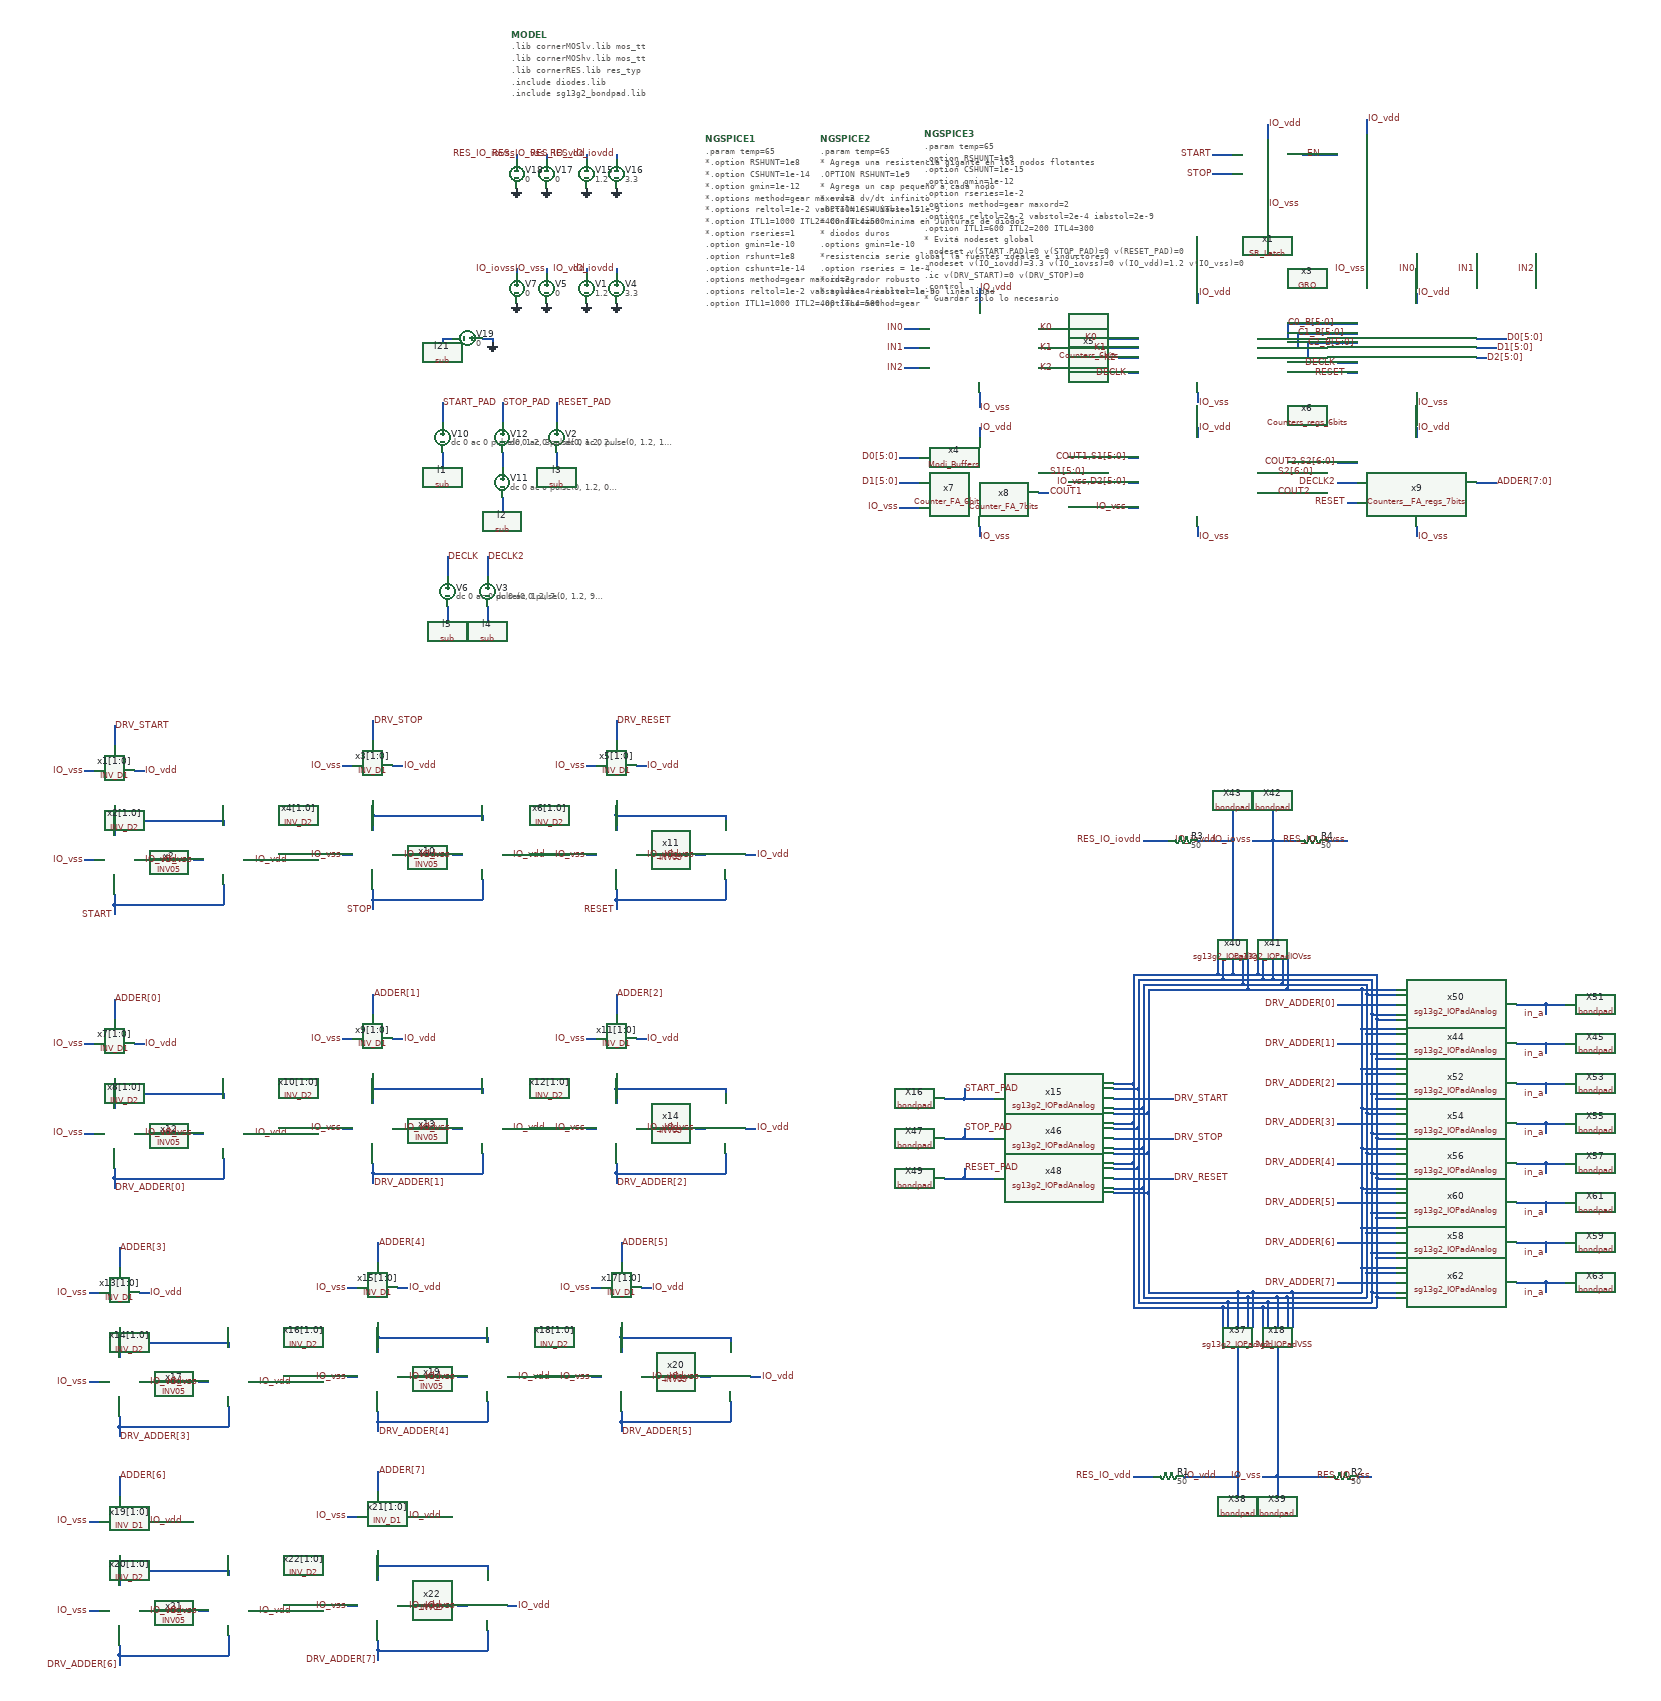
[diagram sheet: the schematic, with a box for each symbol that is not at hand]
v {xschem version=3.4.8RC file_version=1.3}
G {}
K {}
V {}
S {}
F {}
E {}
B 2 30 -920 830 -520 {flags=graph
y2=1.5
ypos1=0
ypos2=2
divy=5
subdivy=1
unity=1
x1=0
divx=5
subdivx=1


dataset=-1
unitx=1
logx=0
logy=0
hilight_wave=0


y1=-0.2
color="17 8 10"
node="IN0
IN1
IN2"
x2=1.1e-07}
B 2 30 -470 830 -70 {flags=graph
y2=1.5
ypos1=0
ypos2=2
divy=5
subdivy=1
unity=1
x1=0
x2=1.1e-07
divx=5
subdivx=1


dataset=-1
unitx=1
logx=0
logy=0
hilight_wave=0


y1=-0.2
color="17 8 10"
node="K0
K1
K2"}
B 2 30 -1360 830 -960 {flags=graph
y2=1.5
ypos1=0
ypos2=2
divy=5
subdivy=1
unity=1
x1=0
x2=1.1e-07
divx=5
subdivx=1


dataset=-1
unitx=1
logx=0
logy=0
hilight_wave=0


y1=-0.2
color="17 8 10 11 15"
node="START
STOP
DECLK
EN
RESET"}
B 2 20 -3140 820 -2740 {flags=graph
y1=-0.024
y2=1.3
ypos1=0
ypos2=2
divy=5
subdivy=1
unity=1
x1=0
x2=1.1e-07
divx=5
subdivx=1


dataset=-1
unitx=1
logx=0
logy=0
hilight_wave=0
color="10 11 11"
node="C0_B[1]
C1_B[1]
C2_B[1]"}
B 2 20 -1810 820 -1410 {flags=graph
y1=-0.4
y2=1.5
ypos1=0
ypos2=2
divy=5
subdivy=1
unity=1
x1=0
x2=1.1e-07
divx=5
subdivx=1


dataset=-1
unitx=1
logx=0
logy=0
hilight_wave=0
color="8 7 11"
node="C0_B[4]
C1_B[4]
C2_B[4]"
rainbow=1}
B 2 20 -2720 820 -2320 {flags=graph
y1=-0.4
y2=1.5
ypos1=0
ypos2=2
divy=5
subdivy=1
unity=1
x1=0
x2=1.1e-07
divx=5
subdivx=1


dataset=-1
unitx=1
logx=0
logy=0
hilight_wave=0
color="7 11 10"
node="C0_B[2]
C1_B[2]
C2_B[2]"}
B 2 20 -2260 820 -1860 {flags=graph
y1=-0.032
y2=1.3
ypos1=0
ypos2=2
divy=5
subdivy=1
unity=1
x1=0
x2=1.1e-07
divx=5
subdivx=1


dataset=-1
unitx=1
logx=0
logy=0
hilight_wave=0


color="11 10 7"
node="C0_B[3]
C1_B[3]
C2_B[3]"}
B 2 850 -3140 1650 -2740 {flags=graph
y1=-0.4
y2=1.5
ypos1=0
ypos2=2
divy=5
subdivy=1
unity=1
x1=0
x2=1.1e-07
divx=5
subdivx=1


dataset=-1
unitx=1
logx=0
logy=0
hilight_wave=0
color=10
node=D0[1]}
B 2 850 -3560 1650 -3160 {flags=graph
y1=-0.4
y2=1.5
ypos1=0
ypos2=2
divy=5
subdivy=1
unity=1
x1=0
x2=1.1e-07
divx=5
subdivx=1


dataset=-1
unitx=1
logx=0
logy=0
hilight_wave=0
color=8
node=D0[0]}
B 2 850 -1810 1650 -1410 {flags=graph
y1=-0.4
y2=1.5
ypos1=0
ypos2=2
divy=5
subdivy=1
unity=1
x1=0
x2=1.1e-07
divx=5
subdivx=1


dataset=-1
unitx=1
logx=0
logy=0
hilight_wave=0
color=8
node=D0[4]}
B 2 850 -2720 1650 -2320 {flags=graph
y1=-0.4
y2=1.5
ypos1=0
ypos2=2
divy=5
subdivy=1
unity=1
x1=0
x2=1.1e-07
divx=5
subdivx=1


dataset=-1
unitx=1
logx=0
logy=0
hilight_wave=0
color=7
node=D0[2]}
B 2 850 -2260 1650 -1860 {flags=graph
y1=-0.4
y2=1.5
ypos1=0
ypos2=2
divy=5
subdivy=1
unity=1
x1=0
x2=1.1e-07
divx=5
subdivx=1


dataset=-1
unitx=1
logx=0
logy=0
hilight_wave=0


color=11
node=D0[3]}
B 2 20 -3560 820 -3160 {flags=graph
y1=-0.4
y2=1.5
ypos1=0
ypos2=2
divy=5
subdivy=1
unity=1
x1=0
x2=1.1e-07
divx=5
subdivx=1


dataset=-1
unitx=1
logx=0
logy=0
hilight_wave=0
color="10 11 11"
node="C0_B[0]
C1_B[0]
C2_B[0]"}
B 2 1680 -3140 2480 -2740 {flags=graph
y1=-0.4
y2=1.5
ypos1=0
ypos2=2
divy=5
subdivy=1
unity=1
x1=0
x2=1.1e-07
divx=5
subdivx=1


dataset=-1
unitx=1
logx=0
logy=0
hilight_wave=0
color=10
node=D1[1]}
B 2 1680 -3560 2480 -3160 {flags=graph
y1=-0.4
y2=1.5
ypos1=0
ypos2=2
divy=5
subdivy=1
unity=1
x1=0
x2=1.1e-07
divx=5
subdivx=1


dataset=-1
unitx=1
logx=0
logy=0
hilight_wave=0
color=8
node=D1[0]}
B 2 1680 -1810 2480 -1410 {flags=graph
y1=-0.4
y2=1.5
ypos1=0
ypos2=2
divy=5
subdivy=1
unity=1
x1=0
x2=1.1e-07
divx=5
subdivx=1


dataset=-1
unitx=1
logx=0
logy=0
hilight_wave=0
color=8
node=D1[4]}
B 2 1680 -2720 2480 -2320 {flags=graph
y1=-0.4
y2=1.5
ypos1=0
ypos2=2
divy=5
subdivy=1
unity=1
x1=0
x2=1.1e-07
divx=5
subdivx=1


dataset=-1
unitx=1
logx=0
logy=0
hilight_wave=0
color=7
node=D1[2]}
B 2 1680 -2260 2480 -1860 {flags=graph
y1=-0.4
y2=1.5
ypos1=0
ypos2=2
divy=5
subdivy=1
unity=1
x1=0
x2=1.1e-07
divx=5
subdivx=1


dataset=-1
unitx=1
logx=0
logy=0
hilight_wave=0


color=11
node=D1[3]}
B 2 2520 -3140 3320 -2740 {flags=graph
y1=-0.4
y2=1.5
ypos1=0
ypos2=2
divy=5
subdivy=1
unity=1
x1=0
x2=1.1e-07
divx=5
subdivx=1


dataset=-1
unitx=1
logx=0
logy=0
hilight_wave=0
color=10
node=D2[1]}
B 2 2520 -3560 3320 -3160 {flags=graph
y1=-0.4
y2=1.5
ypos1=0
ypos2=2
divy=5
subdivy=1
unity=1
x1=0
x2=1.1e-07
divx=5
subdivx=1


dataset=-1
unitx=1
logx=0
logy=0
hilight_wave=0
color=8
node=D2[0]}
B 2 2520 -1810 3320 -1410 {flags=graph
y1=-0.4
y2=1.5
ypos1=0
ypos2=2
divy=5
subdivy=1
unity=1
x1=0
x2=1.1e-07
divx=5
subdivx=1


dataset=-1
unitx=1
logx=0
logy=0
hilight_wave=0
color=8
node=D2[4]}
B 2 2520 -2720 3320 -2320 {flags=graph
y1=-0.4
y2=1.5
ypos1=0
ypos2=2
divy=5
subdivy=1
unity=1
x1=0
x2=1.1e-07
divx=5
subdivx=1


dataset=-1
unitx=1
logx=0
logy=0
hilight_wave=0
color=7
node=D2[2]}
B 2 2520 -2260 3320 -1860 {flags=graph
y1=-0.4
y2=1.5
ypos1=0
ypos2=2
divy=5
subdivy=1
unity=1
x1=0
x2=1.1e-07
divx=5
subdivx=1


dataset=-1
unitx=1
logx=0
logy=0
hilight_wave=0


color=11
node=D2[3]}
B 2 3360 -3140 4160 -2740 {flags=graph
y1=-0.4
y2=1.5
ypos1=0
ypos2=2
divy=5
subdivy=1
unity=1
x1=0
x2=1.1e-07
divx=5
subdivx=1


dataset=-1
unitx=1
logx=0
logy=0
hilight_wave=0
color=10
node=S1[1]}
B 2 3360 -3560 4160 -3160 {flags=graph
y1=-0.4
y2=1.5
ypos1=0
ypos2=2
divy=5
subdivy=1
unity=1
x1=0
x2=1.1e-07
divx=5
subdivx=1


dataset=-1
unitx=1
logx=0
logy=0
hilight_wave=-1
color=8
node=S1[0]}
B 2 3360 -1810 4160 -1410 {flags=graph
y1=-0.4
y2=1.5
ypos1=0
ypos2=2
divy=5
subdivy=1
unity=1
x1=0
x2=1.1e-07
divx=5
subdivx=1


dataset=-1
unitx=1
logx=0
logy=0
hilight_wave=0
color=8
node=S1[4]}
B 2 3360 -1390 4160 -990 {flags=graph
y2=1.5
ypos1=0
ypos2=2
divy=5
subdivy=1
unity=1
x1=0
x2=1.1e-07
divx=5
subdivx=1


dataset=-1
unitx=1
logx=0
logy=0
hilight_wave=0
color=10
node=S1[5]
y1=-0.4}
B 2 3360 -2720 4160 -2320 {flags=graph
y1=-0.4
y2=1.5
ypos1=0
ypos2=2
divy=5
subdivy=1
unity=1
x1=0
x2=1.1e-07
divx=5
subdivx=1


dataset=-1
unitx=1
logx=0
logy=0
hilight_wave=0
color=7
node=S1[2]}
B 2 3360 -2260 4160 -1860 {flags=graph
y1=-0.4
y2=1.5
ypos1=0
ypos2=2
divy=5
subdivy=1
unity=1
x1=0
x2=1.1e-07
divx=5
subdivx=1


dataset=-1
unitx=1
logx=0
logy=0
hilight_wave=0


color=11
node=S1[3]}
B 2 4200 -3140 5000 -2740 {flags=graph
y1=-0.4
y2=1.5
ypos1=0
ypos2=2
divy=5
subdivy=1
unity=1
x1=0
x2=1.1e-07
divx=5
subdivx=1


dataset=-1
unitx=1
logx=0
logy=0
hilight_wave=0
color=10
node=S2[1]}
B 2 4200 -3560 5000 -3160 {flags=graph
y1=-0.4
y2=1.5
ypos1=0
ypos2=2
divy=5
subdivy=1
unity=1
x1=0
x2=1.1e-07
divx=5
subdivx=1


dataset=-1
unitx=1
logx=0
logy=0
hilight_wave=0
color=8
node=S2[0]}
B 2 4200 -1810 5000 -1410 {flags=graph
y1=-0.4
y2=1.5
ypos1=0
ypos2=2
divy=5
subdivy=1
unity=1
x1=0
x2=1.1e-07
divx=5
subdivx=1


dataset=-1
unitx=1
logx=0
logy=0
hilight_wave=0
color=8
node=S2[4]}
B 2 4200 -1390 5000 -990 {flags=graph
y2=1.5
ypos1=0
ypos2=2
divy=5
subdivy=1
unity=1
x1=0
x2=1.1e-07
divx=5
subdivx=1


dataset=-1
unitx=1
logx=0
logy=0
hilight_wave=0
color=10
node=S2[5]
y1=-0.4}
B 2 4200 -2720 5000 -2320 {flags=graph
y1=-0.4
y2=1.5
ypos1=0
ypos2=2
divy=5
subdivy=1
unity=1
x1=0
x2=1.1e-07
divx=5
subdivx=1


dataset=-1
unitx=1
logx=0
logy=0
hilight_wave=-1
color=7
node=S2[2]}
B 2 4200 -2260 5000 -1860 {flags=graph
y1=-0.4
y2=1.5
ypos1=0
ypos2=2
divy=5
subdivy=1
unity=1
x1=0
x2=1.1e-07
divx=5
subdivx=1


dataset=-1
unitx=1
logx=0
logy=0
hilight_wave=0


color=11
node=S2[3]}
B 2 4200 -940 5000 -540 {flags=graph
y2=1.5
ypos1=0
ypos2=2
divy=5
subdivy=1
unity=1
x1=0
x2=1.1e-07
divx=5
subdivx=1


dataset=-1
unitx=1
logx=0
logy=0
hilight_wave=0
y1=-0.4
color=10
node=S2[6]}
B 2 4210 -490 5010 -90 {flags=graph
y2=1.5
ypos1=0
ypos2=2
divy=5
subdivy=1
unity=1
x1=0
x2=1.1e-07
divx=5
subdivx=1


dataset=-1
unitx=1
logx=0
logy=0
hilight_wave=0
y1=-0.4
color=10
node=COUT2}
B 2 5080 -3140 5880 -2740 {flags=graph
y1=-0.4
y2=1.5
ypos1=0
ypos2=2
divy=5
subdivy=1
unity=1
x1=0
x2=1.1e-07
divx=5
subdivx=1


dataset=-1
unitx=1
logx=0
logy=0
hilight_wave=0
color=10
node=ADDER[1]}
B 2 5080 -3560 5880 -3160 {flags=graph
y1=-0.4
y2=1.5
ypos1=0
ypos2=2
divy=5
subdivy=1
unity=1
x1=0
x2=1.1e-07
divx=5
subdivx=1


dataset=-1
unitx=1
logx=0
logy=0
hilight_wave=0
color=8
node=ADDER[0]}
B 2 5080 -1810 5880 -1410 {flags=graph
y1=-0.4
y2=1.5
ypos1=0
ypos2=2
divy=5
subdivy=1
unity=1
x1=0
x2=1.1e-07
divx=5
subdivx=1


dataset=-1
unitx=1
logx=0
logy=0
hilight_wave=0
color=8
node=ADDER[4]}
B 2 5080 -1390 5880 -990 {flags=graph
y2=1.5
ypos1=0
ypos2=2
divy=5
subdivy=1
unity=1
x1=0
x2=1.1e-07
divx=5
subdivx=1


dataset=-1
unitx=1
logx=0
logy=0
hilight_wave=0
color=10
node=ADDER[5]
y1=-0.4}
B 2 5080 -2720 5880 -2320 {flags=graph
y1=-0.4
y2=1.5
ypos1=0
ypos2=2
divy=5
subdivy=1
unity=1
x1=0
x2=1.1e-07
divx=5
subdivx=1


dataset=-1
unitx=1
logx=0
logy=0
hilight_wave=0
color=7
node=ADDER[2]}
B 2 5080 -2260 5880 -1860 {flags=graph
y1=-0.4
y2=1.5
ypos1=0
ypos2=2
divy=5
subdivy=1
unity=1
x1=0
x2=1.1e-07
divx=5
subdivx=1


dataset=-1
unitx=1
logx=0
logy=0
hilight_wave=0


color=11
node=ADDER[3]}
B 2 5080 -940 5880 -540 {flags=graph
y2=1.5
ypos1=0
ypos2=2
divy=5
subdivy=1
unity=1
x1=0
x2=1.1e-07
divx=5
subdivx=1


dataset=-1
unitx=1
logx=0
logy=0
hilight_wave=0
y1=-0.4
color=10
node=ADDER[6]}
B 2 5080 -490 5880 -90 {flags=graph
y2=1.5
ypos1=0
ypos2=2
divy=5
subdivy=1
unity=1
x1=0
x2=1.1e-07
divx=5
subdivx=1


dataset=-1
unitx=1
logx=0
logy=0
hilight_wave=0
y1=-0.4
color=10
node=ADDER[7]}
B 2 -840 -470 -40 -70 {flags=graph
y2=3.5
ypos1=0
ypos2=2
divy=5
subdivy=1
unity=1
x1=0
x2=1.1e-07
divx=5
subdivx=1


dataset=-1
unitx=1
logx=0
logy=0
hilight_wave=0


y1=-0.2
color="17 15 10 8"
node="IO_vdd
IO_vss
IO_iovss
IO_iovdd"}
B 2 -850 -1360 -50 -960 {flags=graph
y2=1.5
ypos1=0
ypos2=2
divy=5
subdivy=1
unity=1
x1=0
x2=1.1e-07
divx=5
subdivx=1


dataset=-1
unitx=1
logx=0
logy=0
hilight_wave=0


y1=-0.2
color="17 8 10 9 15 15"
node="START_PAD
STOP_PAD
DECLK
DECLK2
EN
RESET"}
N 1150 -500 1150 -470 {lab=sub!}
N 930 -190 930 -160 {lab=sub!}
N 1150 -600 1150 -560 {lab=RESET_PAD}
N 930 -290 930 -250 {lab=DECLK}
N 1040 -410 1040 -380 {lab=sub!}
N 920 -500 920 -470 {lab=sub!}
N 1040 -600 1040 -560 {lab=STOP_PAD}
N 920 -600 920 -560 {lab=START_PAD}
N 1040 -500 1040 -470 {lab=#net1}
N 2440 -820 2440 -800 {lab=IO_vdd}
N 2880 -820 2880 -800 {lab=IO_vdd}
N 2440 -620 2440 -600 {lab=IO_vss}
N 2880 -620 2880 -600 {lab=IO_vss}
N 2000 -550 2000 -530 {lab=IO_vdd}
N 2440 -550 2440 -530 {lab=IO_vdd}
N 2000 -350 2000 -330 {lab=IO_vss}
N 2440 -350 2440 -330 {lab=IO_vss}
N 2560 -460 2600 -460 {lab=S2[6:0]}
N 2560 -420 2600 -420 {lab=COUT2}
N 3000 -730 3060 -730 {lab=D0[5:0]}
N 3000 -710 3040 -710 {lab=D1[5:0]}
N 3000 -690 3020 -690 {lab=D2[5:0]}
N 2720 -680 2760 -680 {lab=DECLK}
N 2740 -660 2760 -660 {lab=RESET}
N 2560 -730 2620 -730 {lab=C0_B[5:0]}
N 2560 -710 2640 -710 {lab=C1_B[5:0]}
N 2560 -690 2660 -690 {lab=C2_B[5:0]}
N 2300 -660 2320 -660 {lab=DECLK}
N 2280 -690 2320 -690 {lab=K2}
N 2260 -710 2320 -710 {lab=K1}
N 2240 -730 2320 -730 {lab=K0}
N 1840 -490 1880 -490 {lab=D0[5:0]}
N 1840 -440 1880 -440 {lab=D1[5:0]}
N 1840 -390 1880 -390 {lab=IO_vss}
N 2620 -760 2620 -730 {lab=C0_B[5:0]}
N 2620 -760 2760 -760 {lab=C0_B[5:0]}
N 2640 -740 2640 -710 {lab=C1_B[5:0]}
N 2640 -740 2760 -740 {lab=C1_B[5:0]}
N 2660 -720 2660 -690 {lab=C2_B[5:0]}
N 2660 -720 2760 -720 {lab=C2_B[5:0]}
N 2120 -460 2140 -460 {lab=S1[5:0]}
N 2120 -420 2140 -420 {lab=COUT1}
N 2300 -390 2320 -390 {lab=IO_vss}
N 2300 -440 2320 -440 {lab=IO_vss,D2[5:0]}
N 2300 -490 2320 -490 {lab=COUT1,S1[5:0]}
N 2880 -550 2880 -530 {lab=IO_vdd}
N 2880 -350 2880 -330 {lab=IO_vss}
N 3000 -440 3040 -440 {lab=ADDER[7:0]}
N 2740 -400 2760 -400 {lab=RESET}
N 2720 -440 2760 -440 {lab=DECLK2}
N 2720 -480 2760 -480 {lab=COUT2,S2[6:0]}
N 2470 -1100 2510 -1100 {lab=START}
N 2470 -1060 2510 -1060 {lab=STOP}
N 2580 -1160 2580 -1130 {lab=IO_vdd}
N 2580 -1030 2580 -1000 {lab=IO_vss}
N 2780 -1170 2780 -1140 {lab=IO_vdd}
N 2650 -1100 2720 -1100 {lab=EN}
N 2780 -900 2780 -870 {lab=IO_vss}
N 2880 -900 2880 -870 {lab=IN0}
N 3000 -900 3000 -870 {lab=IN1}
N 3120 -900 3120 -870 {lab=IN2}
N 2000 -620 2000 -590 {lab=IO_vss}
N 2120 -750 2150 -750 {lab=K0}
N 2120 -710 2150 -710 {lab=K1}
N 2120 -670 2150 -670 {lab=K2}
N 1850 -750 1880 -750 {lab=IN0}
N 1850 -710 1880 -710 {lab=IN1}
N 1850 -670 1880 -670 {lab=IN2}
N 2000 -830 2000 -800 {lab=IO_vdd}
N 1010 -190 1010 -160 {lab=sub!}
N 1010 -290 1010 -250 {lab=DECLK2}
N 1210 -1100 1210 -1090 {
lab=#net2}
N 1270 -1100 1270 -1090 {
lab=#net3}
N 1130 -1100 1130 -1090 {
lab=#net4}
N 1070 -1100 1070 -1090 {
lab=#net5}
N 1000 -730 1020 -730 {lab=GND}
N 1020 -730 1020 -720 {lab=GND}
N 920 -730 940 -730 {lab=sub!}
N 920 -730 920 -720 {lab=sub!}
N 2620 580 2770 580 {lab=IO_vdd}
N 2610 570 2780 570 {lab=IO_vss}
N 2590 560 2790 560 {lab=IO_iovss}
N 2560 550 2800 550 {lab=IO_iovdd}
N 2620 1200 2780 1200 {lab=IO_vss}
N 2270 820 2330 820 {lab=IO_vss}
N 2270 780 2320 780 {lab=IO_iovss}
N 2270 770 2310 770 {lab=IO_iovdd}
N 2310 770 2310 850 {lab=IO_iovdd}
N 2330 570 2530 570 {lab=IO_vss}
N 1970 800 2030 800 {lab=START_PAD}
N 1970 780 1970 800 {lab=START_PAD}
N 1930 800 1970 800 {lab=START_PAD}
N 2330 1200 2540 1200 {lab=IO_vss}
N 2570 1560 2600 1560 {lab=IO_vss}
N 2490 1220 2490 1260 {lab=IO_iovdd}
N 2500 1210 2500 1260 {lab=IO_iovss}
N 2540 1200 2540 1260 {lab=IO_vss}
N 2550 1190 2550 1260 {lab=IO_vdd}
N 2570 1220 2570 1260 {lab=IO_iovdd}
N 2580 1210 2580 1260 {lab=IO_iovss}
N 2620 1200 2620 1260 {lab=IO_vss}
N 2630 1190 2630 1260 {lab=IO_vdd}
N 2600 1200 2600 1560 {lab=IO_vss}
N 2600 1560 2600 1600 {lab=IO_vss}
N 2520 1560 2520 1600 {lab=IO_vdd}
N 2520 1190 2520 1560 {lab=IO_vdd}
N 2520 1190 2550 1190 {lab=IO_vdd}
N 2490 1220 2570 1220 {lab=IO_iovdd}
N 2500 1210 2580 1210 {lab=IO_iovss}
N 2600 1200 2620 1200 {lab=IO_vss}
N 2550 1190 2630 1190 {lab=IO_vdd}
N 2540 1200 2600 1200 {lab=IO_vss}
N 2570 1220 2800 1220 {lab=IO_iovdd}
N 2580 1210 2790 1210 {lab=IO_iovss}
N 2630 1190 2770 1190 {lab=IO_vdd}
N 2320 1210 2500 1210 {lab=IO_iovss}
N 2310 1220 2490 1220 {lab=IO_iovdd}
N 2340 1190 2520 1190 {lab=IO_vdd}
N 2540 520 2540 580 {lab=IO_vdd}
N 2530 520 2530 570 {lab=IO_vss}
N 2490 520 2490 560 {lab=IO_iovss}
N 2480 520 2480 550 {lab=IO_iovdd}
N 2620 520 2620 580 {lab=IO_vdd}
N 2610 520 2610 570 {lab=IO_vss}
N 2570 520 2570 560 {lab=IO_iovss}
N 2560 520 2560 550 {lab=IO_iovdd}
N 2510 220 2510 280 {lab=IO_iovdd}
N 2590 220 2590 280 {lab=IO_iovss}
N 2510 280 2510 550 {lab=IO_iovdd}
N 2550 280 2590 280 {lab=IO_iovss}
N 2590 280 2590 560 {lab=IO_iovss}
N 2340 580 2540 580 {lab=IO_vdd}
N 2320 560 2490 560 {lab=IO_iovss}
N 2310 550 2480 550 {lab=IO_iovdd}
N 2540 580 2620 580 {lab=IO_vdd}
N 2530 570 2610 570 {lab=IO_vss}
N 2490 560 2570 560 {lab=IO_iovss}
N 2510 550 2560 550 {lab=IO_iovdd}
N 2480 550 2510 550 {lab=IO_iovdd}
N 2570 560 2590 560 {lab=IO_iovss}
N 2320 560 2320 780 {lab=IO_iovss}
N 2310 550 2310 770 {lab=IO_iovdd}
N 2340 830 2340 910 {lab=IO_vdd}
N 2780 670 2840 670 {lab=IO_vss}
N 2790 710 2840 710 {lab=IO_iovss}
N 2800 720 2840 720 {lab=IO_iovdd}
N 3080 690 3140 690 {lab=#net6}
N 3140 690 3140 710 {lab=#net6}
N 3140 690 3180 690 {lab=#net6}
N 2770 660 2840 660 {lab=IO_vdd}
N 2720 690 2840 690 {lab=#net7}
N 2270 900 2330 900 {lab=IO_vss}
N 2270 860 2320 860 {lab=IO_iovss}
N 2270 850 2310 850 {lab=IO_iovdd}
N 1970 880 2030 880 {lab=STOP_PAD}
N 1970 860 1970 880 {lab=STOP_PAD}
N 1930 880 1970 880 {lab=STOP_PAD}
N 2270 910 2340 910 {lab=IO_vdd}
N 2270 880 2390 880 {lab=DRV_STOP}
N 2330 820 2330 900 {lab=IO_vss}
N 2320 780 2320 860 {lab=IO_iovss}
N 2270 980 2330 980 {lab=IO_vss}
N 2270 940 2320 940 {lab=IO_iovss}
N 2270 930 2310 930 {lab=IO_iovdd}
N 1970 960 2030 960 {lab=RESET_PAD}
N 1970 940 1970 960 {lab=RESET_PAD}
N 1930 960 1970 960 {lab=RESET_PAD}
N 2270 990 2340 990 {lab=IO_vdd}
N 2270 960 2390 960 {lab=DRV_RESET}
N 2330 900 2330 980 {lab=IO_vss}
N 2320 860 2320 940 {lab=IO_iovss}
N 2310 850 2310 930 {lab=IO_iovdd}
N 2340 910 2340 990 {lab=IO_vdd}
N 2780 590 2840 590 {lab=IO_vss}
N 2790 630 2840 630 {lab=IO_iovss}
N 2800 640 2840 640 {lab=IO_iovdd}
N 3080 610 3140 610 {lab=#net8}
N 3140 610 3140 630 {lab=#net8}
N 3140 610 3180 610 {lab=#net8}
N 2770 580 2840 580 {lab=IO_vdd}
N 2720 610 2840 610 {lab=#net9}
N 2780 750 2840 750 {lab=IO_vss}
N 2790 790 2840 790 {lab=IO_iovss}
N 2800 800 2840 800 {lab=IO_iovdd}
N 3080 770 3140 770 {lab=#net10}
N 3140 770 3140 790 {lab=#net10}
N 3140 770 3180 770 {lab=#net10}
N 2770 740 2840 740 {lab=IO_vdd}
N 2720 770 2840 770 {lab=#net11}
N 2780 830 2840 830 {lab=IO_vss}
N 2790 870 2840 870 {lab=IO_iovss}
N 2800 880 2840 880 {lab=IO_iovdd}
N 3080 850 3140 850 {lab=#net12}
N 3140 850 3140 870 {lab=#net12}
N 3140 850 3180 850 {lab=#net12}
N 2770 820 2840 820 {lab=IO_vdd}
N 2720 850 2840 850 {lab=#net13}
N 2780 910 2840 910 {lab=IO_vss}
N 2800 960 2840 960 {lab=IO_iovdd}
N 3080 930 3140 930 {lab=#net14}
N 3140 930 3140 950 {lab=#net14}
N 3140 930 3180 930 {lab=#net14}
N 2770 900 2840 900 {lab=IO_vdd}
N 2720 930 2840 930 {lab=#net15}
N 2780 590 2780 670 {lab=IO_vss}
N 2790 630 2790 710 {lab=IO_iovss}
N 2800 640 2800 720 {lab=IO_iovdd}
N 2770 580 2770 660 {lab=IO_vdd}
N 2780 570 2780 590 {lab=IO_vss}
N 2790 560 2790 630 {lab=IO_iovss}
N 2800 550 2800 640 {lab=IO_iovdd}
N 2780 670 2780 750 {lab=IO_vss}
N 2790 710 2790 790 {lab=IO_iovss}
N 2800 720 2800 800 {lab=IO_iovdd}
N 2770 660 2770 740 {lab=IO_vdd}
N 2780 750 2780 830 {lab=IO_vss}
N 2790 790 2790 870 {lab=IO_iovss}
N 2800 800 2800 880 {lab=IO_iovdd}
N 2770 740 2770 820 {lab=IO_vdd}
N 2780 830 2780 910 {lab=IO_vss}
N 2790 950 2790 1030 {lab=IO_iovss}
N 2770 820 2770 900 {lab=IO_vdd}
N 2780 1070 2840 1070 {lab=IO_vss}
N 2790 1110 2840 1110 {lab=IO_iovss}
N 2800 1120 2840 1120 {lab=IO_iovdd}
N 3080 1090 3140 1090 {lab=#net16}
N 3140 1090 3140 1110 {lab=#net16}
N 3140 1090 3180 1090 {lab=#net16}
N 2770 1060 2840 1060 {lab=IO_vdd}
N 2720 1090 2840 1090 {lab=#net17}
N 2780 990 2840 990 {lab=IO_vss}
N 2790 1030 2840 1030 {lab=IO_iovss}
N 2800 1040 2840 1040 {lab=IO_iovdd}
N 3080 1010 3140 1010 {lab=#net18}
N 3140 1010 3140 1030 {lab=#net18}
N 3140 1010 3180 1010 {lab=#net18}
N 2770 980 2840 980 {lab=IO_vdd}
N 2720 1010 2840 1010 {lab=#net19}
N 2780 1150 2840 1150 {lab=IO_vss}
N 2790 1190 2840 1190 {lab=IO_iovss}
N 2800 1200 2840 1200 {lab=IO_iovdd}
N 3080 1170 3140 1170 {lab=#net20}
N 3140 1170 3140 1190 {lab=#net20}
N 3140 1170 3180 1170 {lab=#net20}
N 2770 1140 2840 1140 {lab=IO_vdd}
N 2720 1170 2840 1170 {lab=#net21}
N 2780 990 2780 1070 {lab=IO_vss}
N 2790 1030 2790 1110 {lab=IO_iovss}
N 2800 1040 2800 1120 {lab=IO_iovdd}
N 2770 980 2770 1060 {lab=IO_vdd}
N 2800 960 2800 1040 {lab=IO_iovdd}
N 2780 1070 2780 1150 {lab=IO_vss}
N 2790 1110 2790 1190 {lab=IO_iovss}
N 2800 1120 2800 1200 {lab=IO_iovdd}
N 2770 1060 2770 1140 {lab=IO_vdd}
N 2770 900 2770 980 {lab=IO_vdd}
N 2780 910 2780 990 {lab=IO_vss}
N 2800 880 2800 960 {lab=IO_iovdd}
N 2780 1150 2780 1200 {lab=IO_vss}
N 2330 980 2330 1200 {lab=IO_vss}
N 2800 1200 2800 1220 {lab=IO_iovdd}
N 2790 1190 2790 1210 {lab=IO_iovss}
N 2770 1140 2770 1190 {lab=IO_vdd}
N 2320 940 2320 1210 {lab=IO_iovss}
N 2310 930 2310 1220 {lab=IO_iovdd}
N 2340 990 2340 1190 {lab=IO_vdd}
N 2790 950 2840 950 {lab=IO_iovss}
N 2790 870 2790 950 {lab=IO_iovss}
N 2270 830 2340 830 {lab=IO_vdd}
N 2330 570 2330 820 {lab=IO_vss}
N 2340 580 2340 830 {lab=IO_vdd}
N 2270 800 2390 800 {lab=DRV_START}
N 300 140 320 140 {lab=IO_vdd}
N 200 140 220 140 {lab=IO_vss}
N 200 320 220 320 {lab=IO_vss}
N 300 320 320 320 {lab=IO_vdd}
N 420 320 440 320 {lab=IO_vss}
N 520 320 540 320 {lab=IO_vdd}
N 260 390 260 410 {lab=START}
N 260 410 480 410 {lab=START}
N 260 240 260 270 {lab=#net22}
N 260 50 260 90 {lab=DRV_START}
N 260 410 260 430 {lab=START}
N 480 240 480 250 {lab=#net22}
N 260 240 480 240 {lab=#net22}
N 260 210 260 240 {lab=#net22}
N 480 370 480 410 {lab=START}
N 820 130 840 130 {lab=IO_vdd}
N 720 130 740 130 {lab=IO_vss}
N 720 310 740 310 {lab=IO_vss}
N 820 310 840 310 {lab=IO_vdd}
N 940 310 960 310 {lab=IO_vss}
N 1040 310 1060 310 {lab=IO_vdd}
N 780 380 780 400 {lab=STOP}
N 780 400 1000 400 {lab=STOP}
N 780 230 780 260 {lab=#net23}
N 780 40 780 80 {lab=DRV_STOP}
N 780 400 780 420 {lab=STOP}
N 1000 230 1000 240 {lab=#net23}
N 780 230 1000 230 {lab=#net23}
N 780 200 780 230 {lab=#net23}
N 1000 360 1000 400 {lab=STOP}
N 1310 130 1330 130 {lab=IO_vdd}
N 1210 130 1230 130 {lab=IO_vss}
N 1210 310 1230 310 {lab=IO_vss}
N 1310 310 1330 310 {lab=IO_vdd}
N 1430 310 1450 310 {lab=IO_vss}
N 1530 310 1550 310 {lab=IO_vdd}
N 1270 380 1270 400 {lab=RESET}
N 1270 400 1490 400 {lab=RESET}
N 1270 230 1270 260 {lab=#net24}
N 1270 40 1270 80 {lab=DRV_RESET}
N 1270 400 1270 420 {lab=RESET}
N 1490 230 1490 240 {lab=#net24}
N 1270 230 1490 230 {lab=#net24}
N 1270 200 1270 230 {lab=#net24}
N 1490 360 1490 400 {lab=RESET}
N 300 690 320 690 {lab=IO_vdd}
N 200 690 220 690 {lab=IO_vss}
N 200 870 220 870 {lab=IO_vss}
N 300 870 320 870 {lab=IO_vdd}
N 420 870 440 870 {lab=IO_vss}
N 520 870 540 870 {lab=IO_vdd}
N 260 940 260 960 {lab=DRV_ADDER[0]}
N 260 960 480 960 {lab=DRV_ADDER[0]}
N 260 790 260 820 {lab=#net25}
N 260 600 260 640 {lab=ADDER[0]}
N 260 960 260 980 {lab=DRV_ADDER[0]}
N 480 790 480 800 {lab=#net25}
N 260 790 480 790 {lab=#net25}
N 260 760 260 790 {lab=#net25}
N 480 920 480 960 {lab=DRV_ADDER[0]}
N 820 680 840 680 {lab=IO_vdd}
N 720 680 740 680 {lab=IO_vss}
N 720 860 740 860 {lab=IO_vss}
N 820 860 840 860 {lab=IO_vdd}
N 940 860 960 860 {lab=IO_vss}
N 1040 860 1060 860 {lab=IO_vdd}
N 780 930 780 950 {lab=DRV_ADDER[1]}
N 780 950 1000 950 {lab=DRV_ADDER[1]}
N 780 780 780 810 {lab=#net26}
N 780 590 780 630 {lab=ADDER[1]}
N 780 950 780 970 {lab=DRV_ADDER[1]}
N 1000 780 1000 790 {lab=#net26}
N 780 780 1000 780 {lab=#net26}
N 780 750 780 780 {lab=#net26}
N 1000 910 1000 950 {lab=DRV_ADDER[1]}
N 1310 680 1330 680 {lab=IO_vdd}
N 1210 680 1230 680 {lab=IO_vss}
N 1210 860 1230 860 {lab=IO_vss}
N 1310 860 1330 860 {lab=IO_vdd}
N 1430 860 1450 860 {lab=IO_vss}
N 1530 860 1550 860 {lab=IO_vdd}
N 1270 930 1270 950 {lab=DRV_ADDER[2]}
N 1270 950 1490 950 {lab=DRV_ADDER[2]}
N 1270 780 1270 810 {lab=#net27}
N 1270 590 1270 630 {lab=ADDER[2]}
N 1270 950 1270 970 {lab=DRV_ADDER[2]}
N 1490 780 1490 790 {lab=#net27}
N 1270 780 1490 780 {lab=#net27}
N 1270 750 1270 780 {lab=#net27}
N 1490 910 1490 950 {lab=DRV_ADDER[2]}
N 310 1190 330 1190 {lab=IO_vdd}
N 210 1190 230 1190 {lab=IO_vss}
N 210 1370 230 1370 {lab=IO_vss}
N 310 1370 330 1370 {lab=IO_vdd}
N 430 1370 450 1370 {lab=IO_vss}
N 530 1370 550 1370 {lab=IO_vdd}
N 270 1440 270 1460 {lab=DRV_ADDER[3]}
N 270 1460 490 1460 {lab=DRV_ADDER[3]}
N 270 1290 270 1320 {lab=#net28}
N 270 1100 270 1140 {lab=ADDER[3]}
N 270 1460 270 1480 {lab=DRV_ADDER[3]}
N 490 1290 490 1300 {lab=#net28}
N 270 1290 490 1290 {lab=#net28}
N 270 1260 270 1290 {lab=#net28}
N 490 1420 490 1460 {lab=DRV_ADDER[3]}
N 830 1180 850 1180 {lab=IO_vdd}
N 730 1180 750 1180 {lab=IO_vss}
N 730 1360 750 1360 {lab=IO_vss}
N 830 1360 850 1360 {lab=IO_vdd}
N 950 1360 970 1360 {lab=IO_vss}
N 1050 1360 1070 1360 {lab=IO_vdd}
N 790 1430 790 1450 {lab=DRV_ADDER[4]}
N 790 1450 1010 1450 {lab=DRV_ADDER[4]}
N 790 1280 790 1310 {lab=#net29}
N 790 1090 790 1130 {lab=ADDER[4]}
N 790 1450 790 1470 {lab=DRV_ADDER[4]}
N 1010 1280 1010 1290 {lab=#net29}
N 790 1280 1010 1280 {lab=#net29}
N 790 1250 790 1280 {lab=#net29}
N 1010 1410 1010 1450 {lab=DRV_ADDER[4]}
N 1320 1180 1340 1180 {lab=IO_vdd}
N 1220 1180 1240 1180 {lab=IO_vss}
N 1220 1360 1240 1360 {lab=IO_vss}
N 1320 1360 1340 1360 {lab=IO_vdd}
N 1440 1360 1460 1360 {lab=IO_vss}
N 1540 1360 1560 1360 {lab=IO_vdd}
N 1280 1430 1280 1450 {lab=DRV_ADDER[5]}
N 1280 1450 1500 1450 {lab=DRV_ADDER[5]}
N 1280 1280 1280 1310 {lab=#net30}
N 1280 1090 1280 1130 {lab=ADDER[5]}
N 1280 1450 1280 1470 {lab=DRV_ADDER[5]}
N 1500 1280 1500 1290 {lab=#net30}
N 1280 1280 1500 1280 {lab=#net30}
N 1280 1250 1280 1280 {lab=#net30}
N 1500 1410 1500 1450 {lab=DRV_ADDER[5]}
N 310 1650 330 1650 {lab=IO_vdd}
N 210 1650 230 1650 {lab=IO_vss}
N 210 1830 230 1830 {lab=IO_vss}
N 310 1830 330 1830 {lab=IO_vdd}
N 430 1830 450 1830 {lab=IO_vss}
N 530 1830 550 1830 {lab=IO_vdd}
N 270 1900 270 1920 {lab=DRV_ADDER[6]}
N 270 1920 490 1920 {lab=DRV_ADDER[6]}
N 270 1750 270 1780 {lab=#net31}
N 270 1560 270 1600 {lab=ADDER[6]}
N 270 1920 270 1940 {lab=DRV_ADDER[6]}
N 490 1750 490 1760 {lab=#net31}
N 270 1750 490 1750 {lab=#net31}
N 270 1720 270 1750 {lab=#net31}
N 490 1880 490 1920 {lab=DRV_ADDER[6]}
N 830 1640 850 1640 {lab=IO_vdd}
N 730 1640 750 1640 {lab=IO_vss}
N 730 1820 750 1820 {lab=IO_vss}
N 830 1820 850 1820 {lab=IO_vdd}
N 950 1820 970 1820 {lab=IO_vss}
N 1050 1820 1070 1820 {lab=IO_vdd}
N 790 1890 790 1910 {lab=DRV_ADDER[7]}
N 790 1910 1010 1910 {lab=DRV_ADDER[7]}
N 790 1740 790 1770 {lab=#net32}
N 790 1550 790 1590 {lab=ADDER[7]}
N 790 1910 790 1930 {lab=DRV_ADDER[7]}
N 1010 1740 1010 1750 {lab=#net32}
N 790 1740 1010 1740 {lab=#net32}
N 790 1710 790 1740 {lab=#net32}
N 1010 1870 1010 1910 {lab=DRV_ADDER[7]}
N 2410 1560 2520 1560 {lab=IO_vdd}
N 2310 1560 2350 1560 {lab=#net33}
N 2600 1560 2700 1560 {lab=IO_vss}
N 2760 1560 2790 1560 {lab=#net34}
N 2440 280 2510 280 {lab=IO_iovdd}
N 2330 280 2380 280 {lab=#net35}
N 2590 280 2640 280 {lab=IO_iovss}
N 2700 280 2740 280 {lab=#net36}
N 1210 -870 1210 -860 {
lab=IO_vdd}
N 1270 -870 1270 -860 {
lab=IO_iovdd}
N 1130 -870 1130 -860 {
lab=IO_vss}
N 1070 -870 1070 -860 {
lab=IO_iovss}
C {devices/launcher.sym} 1515 -1215 0 0 {name=h5
descr="load waves Ctrl + left click" 
tclcommand="xschem raw_read $netlist_dir/tb_TOP_io.raw tran"
}
C {devices/launcher.sym} 1515 -1275 0 0 {name=h1
descr="simulate" 
tclcommand="xschem save; xschem netlist; xschem simulate"
}
C {vsource.sym} 1150 -530 0 0 {name=V2 value="dc 0 ac 0 pulse(0, 1.2, 190n, 900p, 900p, 5n, 0)" savecurrent=false
}
C {lab_wire.sym} 1150 -600 0 1 {name=p6 sig_type=std_logic lab=RESET_PAD
}
C {lab_wire.sym} 930 -290 0 1 {name=p4 sig_type=std_logic lab=DECLK
}
C {vsource.sym} 930 -220 0 0 {name=V6 value="dc 0 ac 0 pulse(0, 1.2, 75n, 5n, 5n, 100n)" savecurrent=false
}
C {lab_wire.sym} 1040 -600 0 1 {name=p55 sig_type=std_logic lab=STOP_PAD
}
C {lab_wire.sym} 920 -600 0 1 {name=p56 sig_type=std_logic lab=START_PAD
}
C {vsource.sym} 920 -530 0 0 {name=V10 value="dc 0 ac 0 pulse(0, 1.2, 35n, 5n, 5n, 21n)" savecurrent=false
}
C {vsource.sym} 1040 -440 0 0 {name=V11 value="dc 0 ac 0 pulse(0, 1.2, 0, 5n, 5n, 5n, 0)" savecurrent=false
}
C {vsource.sym} 1040 -530 0 0 {name=V12 value="dc 0 ac 0 pulse(0, 1.2, 20n, 5n, 5n, 900n)" savecurrent=false
}
C {code.sym} 1450 -1130 0 0 {name=NGSPICE1 only_toplevel=true 
value="
.param temp=65

*.option RSHUNT=1e8
*.option CSHUNT=1e-14
*.option gmin=1e-12
*.options method=gear maxord=2
*.options reltol=1e-2 vabstol=1e-4 iabstol=1e-9
*.option ITL1=1000 ITL2=400 ITL4=500
*.option rseries=1


.option gmin=1e-10
.option rshunt=1e8
.option cshunt=1e-14
.options method=gear maxord=2
.options reltol=1e-2 vabstol=1e-4 iabstol=1e-9
.option ITL1=1000 ITL2=400 ITL4=500
.option rseries=1



*vntol=1e-5
*.option rseries = 1e-4
*.option ITL1 = 600
*.option ITL2 = 400
*.option ITL4 = 300
*.option maxord=2
*.options pivtol=1e-10
*.options chgtol=1e-13

.control
* Sources
save v(START) v(STOP) v(DECLK) v(RESET)
save v(IO_iovss) v(IO_iovdd) v(IO_vss) v(IO_vdd)

* GRO
save v(IN0) v(IN1) v(IN2)

* Buffers
save v(K0) v(K1) v(K2)

* Counters Reg (BUS → SIEMPRE con comillas)
save v("D0[0]") v("D0[1]") v("D0[2]") 
save v("D0[3]") v("D0[4]") v("D0[5]") 
save v("D1[0]") v("D1[1]") v("D1[2]")
save v("D1[3]") v("D1[4]") v("D1[5]")
save v("D2[0]") v("D2[1]") v("D2[2]")
save v("D2[3]") v("D2[4]") v("D2[5]")

* FA
save v("S1[0]") v("S1[1]") v("S1[2]") 
save v("S1[3]") v("S1[4]") v("S1[5]") 
save v(COUT1) 
save v("S2[0]") v("S2[1]") v("S2[2]") 
save v("S2[3]") v("S2[4]") v("S2[5]") v("S2[6]")
save v(COUT2)

* FA Regs
save v("ADDER[0]") v("ADDER[1]") v("ADDER[2]")
save v("ADDER[3]") v("ADDER[4]") v("ADDER[5]")
save v("ADDER[6]") v("ADDER[7]")

tran 5p 50n 0 5p uic


write tb_TOP_io.raw

.endc
"
spice_ignore=true}
C {Counters_6bits.sym} 2220 -560 0 0 {name=x5
}
C {Counters_regs_6bits.sym} 2660 -530 0 0 {name=x6
}
C {Counter_FA_6bits.sym} 1860 -350 0 0 {name=x7
}
C {Counter_FA_7bits.sym} 2060 -270 0 0 {name=x8
}
C {lab_wire.sym} 2260 -710 3 0 {name=p18 sig_type=std_logic lab=K1
}
C {lab_wire.sym} 2240 -730 3 0 {name=p17 sig_type=std_logic lab=K0
}
C {lab_wire.sym} 2280 -690 3 0 {name=p19 sig_type=std_logic lab=K2
}
C {lab_wire.sym} 2300 -660 3 0 {name=p20 sig_type=std_logic lab=DECLK
}
C {lab_wire.sym} 2720 -680 3 0 {name=p21 sig_type=std_logic lab=DECLK
}
C {lab_wire.sym} 2740 -660 3 0 {name=p22 sig_type=std_logic lab=RESET
}
C {lab_wire.sym} 2300 -490 0 0 {name=p23 sig_type=std_logic lab=COUT1,S1[5:0]
}
C {lab_wire.sym} 3060 -730 0 1 {name=p24 sig_type=std_logic lab=D0[5:0]
}
C {lab_wire.sym} 3040 -710 0 1 {name=p25 sig_type=std_logic lab=D1[5:0]
}
C {lab_wire.sym} 3020 -690 0 1 {name=p26 sig_type=std_logic lab=D2[5:0]
}
C {lab_wire.sym} 1840 -490 0 0 {name=p27 sig_type=std_logic lab=D0[5:0]
}
C {lab_wire.sym} 1840 -440 0 0 {name=p28 sig_type=std_logic lab=D1[5:0]
}
C {lab_wire.sym} 2300 -440 0 0 {name=p29 sig_type=std_logic lab=IO_vss,D2[5:0]
}
C {lab_wire.sym} 1840 -390 0 0 {name=p30 sig_type=std_logic lab=IO_vss
}
C {lab_wire.sym} 2300 -390 0 0 {name=p31 sig_type=std_logic lab=IO_vss
}
C {lab_wire.sym} 2140 -460 0 1 {name=p32 sig_type=std_logic lab=S1[5:0]
}
C {lab_wire.sym} 2140 -420 0 1 {name=p33 sig_type=std_logic lab=COUT1
}
C {lab_wire.sym} 2600 -420 0 1 {name=p35 sig_type=std_logic lab=COUT2
}
C {lab_wire.sym} 2720 -440 3 0 {name=p34 sig_type=std_logic lab=DECLK2
}
C {lab_wire.sym} 2740 -400 3 0 {name=p38 sig_type=std_logic lab=RESET
}
C {Counters__FA_regs_7bits.sym} 2720 -320 0 0 {name=x9
}
C {lab_wire.sym} 3040 -440 0 1 {name=p39 sig_type=std_logic lab=ADDER[7:0]
}
C {lab_wire.sym} 2600 -460 0 1 {name=p7 sig_type=std_logic lab=S2[6:0]
}
C {lab_wire.sym} 2720 -480 0 0 {name=p8 sig_type=std_logic lab=COUT2,S2[6:0]
}
C {SR_Latch.sym} 2490 -990 0 0 {name=x1
}
C {lab_wire.sym} 2470 -1100 0 0 {name=p62 sig_type=std_logic lab=START
}
C {lab_wire.sym} 2470 -1060 0 0 {name=p63 sig_type=std_logic lab=STOP
}
C {lab_wire.sym} 2690 -1100 0 0 {name=p64 sig_type=std_logic lab=EN
}
C {GRO.sym} 2720 -880 0 0 {name=x3
}
C {lab_wire.sym} 2880 -870 0 0 {name=p66 sig_type=std_logic lab=IN0
}
C {lab_wire.sym} 3000 -870 0 0 {name=p67 sig_type=std_logic lab=IN1
}
C {lab_wire.sym} 3120 -870 0 0 {name=p68 sig_type=std_logic lab=IN2
}
C {Modi_Buffers.sym} 1780 -530 0 0 {name=x4
}
C {lab_wire.sym} 2150 -750 3 1 {name=p70 sig_type=std_logic lab=K0
}
C {lab_wire.sym} 2150 -710 3 1 {name=p71 sig_type=std_logic lab=K1
}
C {lab_wire.sym} 2150 -670 3 1 {name=p72 sig_type=std_logic lab=K2
}
C {lab_wire.sym} 1850 -750 1 0 {name=p73 sig_type=std_logic lab=IN0
}
C {lab_wire.sym} 1850 -710 1 0 {name=p74 sig_type=std_logic lab=IN1
}
C {lab_wire.sym} 1850 -670 1 0 {name=p75 sig_type=std_logic lab=IN2
}
C {lab_wire.sym} 2620 -760 0 1 {name=p40 sig_type=std_logic lab=C0_B[5:0]
}
C {lab_wire.sym} 2640 -740 0 1 {name=p41 sig_type=std_logic lab=C1_B[5:0]
}
C {lab_wire.sym} 2660 -720 0 1 {name=p42 sig_type=std_logic lab=C2_B[5:0]
}
C {lab_wire.sym} 1010 -290 0 1 {name=p46 sig_type=std_logic lab=DECLK2
}
C {vsource.sym} 1010 -220 0 0 {name=V3 value="dc 0 ac 0 pulse(0, 1.2, 90n, 5n, 5n, 100n)" savecurrent=false
}
C {devices/code_shown.sym} 1060 -1340 0 0 {name=MODEL only_toplevel=true
format="tcleval( @value )"
value="
.lib cornerMOSlv.lib mos_tt
.lib cornerMOShv.lib mos_tt
.lib cornerRES.lib res_typ
.include diodes.lib
.include sg13g2_bondpad.lib
"}
C {vsource.sym} 1210 -1060 0 0 {name=V15 value=1.2
spice_ignore=true}
C {gnd.sym} 1210 -1030 0 0 {name=l15 lab=GND
spice_ignore=true}
C {lab_pin.sym} 1210 -1100 1 0 {name=p90 sig_type=std_logic lab=RES_IO_vdd
spice_ignore=true}
C {vsource.sym} 1270 -1060 0 0 {name=V16 value=3.3
spice_ignore=true}
C {gnd.sym} 1270 -1030 0 0 {name=l16 lab=GND
spice_ignore=true}
C {lab_pin.sym} 1270 -1100 1 0 {name=p91 sig_type=std_logic lab=RES_IO_iovdd
spice_ignore=true}
C {vsource.sym} 1130 -1060 0 0 {name=V17 value=0 savecurrent=false
spice_ignore=true}
C {gnd.sym} 1130 -1030 0 0 {name=l17 lab=GND
spice_ignore=true}
C {lab_pin.sym} 1130 -1100 1 0 {name=p92 sig_type=std_logic lab=RES_IO_vss
spice_ignore=true}
C {vsource.sym} 1070 -1060 0 0 {name=V18 value=0 savecurrent=false
spice_ignore=true}
C {gnd.sym} 1070 -1030 0 0 {name=l18 lab=GND
spice_ignore=true}
C {lab_pin.sym} 1070 -1100 1 0 {name=p93 sig_type=std_logic lab=RES_IO_iovss
spice_ignore=true}
C {sg13g2_pr/sub.sym} 920 -720 0 0 {name=l21 lab=sub!}
C {gnd.sym} 1020 -720 0 0 {name=l22 lab=GND}
C {vsource.sym} 970 -730 1 0 {name=V19 value=0 savecurrent=false}
C {lab_pin.sym} 2000 -830 2 0 {name=p1 sig_type=std_logic lab=IO_vdd
}
C {lab_pin.sym} 2580 -1160 2 0 {name=p2 sig_type=std_logic lab=IO_vdd
}
C {lab_pin.sym} 2780 -1170 2 0 {name=p5 sig_type=std_logic lab=IO_vdd
}
C {lab_pin.sym} 2440 -820 2 0 {name=p13 sig_type=std_logic lab=IO_vdd
}
C {lab_pin.sym} 2880 -820 2 0 {name=p14 sig_type=std_logic lab=IO_vdd
}
C {lab_pin.sym} 2000 -550 2 0 {name=p15 sig_type=std_logic lab=IO_vdd
}
C {lab_pin.sym} 2440 -550 2 0 {name=p16 sig_type=std_logic lab=IO_vdd
}
C {lab_pin.sym} 2880 -550 2 0 {name=p36 sig_type=std_logic lab=IO_vdd
}
C {lab_pin.sym} 2000 -590 2 0 {name=p9 sig_type=std_logic lab=IO_vss
}
C {lab_pin.sym} 2440 -600 2 0 {name=p10 sig_type=std_logic lab=IO_vss
}
C {lab_pin.sym} 2880 -600 2 0 {name=p11 sig_type=std_logic lab=IO_vss
}
C {lab_pin.sym} 2000 -330 2 0 {name=p12 sig_type=std_logic lab=IO_vss
}
C {lab_pin.sym} 2440 -330 2 0 {name=p37 sig_type=std_logic lab=IO_vss
}
C {lab_pin.sym} 2880 -330 2 0 {name=p44 sig_type=std_logic lab=IO_vss
}
C {lab_pin.sym} 2580 -1000 2 0 {name=p61 sig_type=std_logic lab=IO_vss
}
C {lab_pin.sym} 2780 -870 2 1 {name=p43 sig_type=std_logic lab=IO_vss
}
C {sg13g2_IOPadAnalog.sym} 2150 800 0 1 {name=x15
}
C {sg13g2_pr/bondpad.sym} 1890 800 3 1 {name=X16
model=bondpad
spiceprefix=X
size=80u
shape=0
padtype=0
}
C {lab_pin.sym} 2390 800 0 1 {name=p87 sig_type=std_logic lab=DRV_START
}
C {lab_pin.sym} 1970 780 2 0 {name=p88 sig_type=std_logic lab=START_PAD
}
C {lab_pin.sym} 2480 1560 3 1 {name=p89 sig_type=std_logic lab=IO_vdd
}
C {lab_pin.sym} 2570 1560 1 0 {name=p94 sig_type=std_logic lab=IO_vss
}
C {sg13g2_IOPadVSS.sym} 2600 1380 3 1 {name=x18
}
C {sg13g2_IOPadVdd.sym} 2520 1380 3 1 {name=x37
}
C {sg13g2_pr/bondpad.sym} 2520 1640 2 1 {name=X38
model=bondpad
spiceprefix=X
size=80u
shape=0
padtype=0
}
C {sg13g2_pr/bondpad.sym} 2600 1640 2 1 {name=X39
model=bondpad
spiceprefix=X
size=80u
shape=0
padtype=0
}
C {lab_pin.sym} 2480 280 1 0 {name=p95 sig_type=std_logic lab=IO_iovdd
}
C {lab_pin.sym} 2550 280 1 0 {name=p96 sig_type=std_logic lab=IO_iovss
}
C {sg13g2_IOPadIOVdd.sym} 2510 400 3 0 {name=x40
}
C {sg13g2_IOPadIOVss.sym} 2590 400 3 0 {name=x41
}
C {sg13g2_pr/bondpad.sym} 2590 180 0 0 {name=X42
model=bondpad
spiceprefix=X
size=80u
shape=0
padtype=0
}
C {sg13g2_pr/bondpad.sym} 2510 180 0 0 {name=X43
model=bondpad
spiceprefix=X
size=80u
shape=0
padtype=0
}
C {sg13g2_IOPadAnalog.sym} 2960 690 2 1 {name=x44
spice_ignore=true}
C {sg13g2_pr/bondpad.sym} 3220 690 1 1 {name=X45
model=bondpad
spiceprefix=X
size=80u
shape=0
padtype=0
spice_ignore=true}
C {lab_pin.sym} 2720 690 2 1 {name=p97 sig_type=std_logic lab=DRV_ADDER[1]
spice_ignore=true}
C {lab_pin.sym} 3140 710 3 0 {name=p98 sig_type=std_logic lab=in_a
spice_ignore=true}
C {sg13g2_IOPadAnalog.sym} 2150 880 0 1 {name=x46
}
C {sg13g2_pr/bondpad.sym} 1890 880 3 1 {name=X47
model=bondpad
spiceprefix=X
size=80u
shape=0
padtype=0
}
C {lab_pin.sym} 2390 880 0 1 {name=p99 sig_type=std_logic lab=DRV_STOP
}
C {lab_pin.sym} 1970 860 2 0 {name=p100 sig_type=std_logic lab=STOP_PAD
}
C {sg13g2_IOPadAnalog.sym} 2150 960 0 1 {name=x48
}
C {sg13g2_pr/bondpad.sym} 1890 960 3 1 {name=X49
model=bondpad
spiceprefix=X
size=80u
shape=0
padtype=0
}
C {lab_pin.sym} 2390 960 0 1 {name=p101 sig_type=std_logic lab=DRV_RESET
}
C {lab_pin.sym} 1970 940 2 0 {name=p102 sig_type=std_logic lab=RESET_PAD
}
C {sg13g2_IOPadAnalog.sym} 2960 610 2 1 {name=x50
spice_ignore=true}
C {sg13g2_pr/bondpad.sym} 3220 610 1 1 {name=X51
model=bondpad
spiceprefix=X
size=80u
shape=0
padtype=0
spice_ignore=true}
C {lab_pin.sym} 2720 610 2 1 {name=p119 sig_type=std_logic lab=DRV_ADDER[0]
spice_ignore=true}
C {lab_pin.sym} 3140 630 3 0 {name=p120 sig_type=std_logic lab=in_a
spice_ignore=true}
C {sg13g2_IOPadAnalog.sym} 2960 770 2 1 {name=x52
spice_ignore=true}
C {sg13g2_pr/bondpad.sym} 3220 770 1 1 {name=X53
model=bondpad
spiceprefix=X
size=80u
shape=0
padtype=0
spice_ignore=true}
C {lab_pin.sym} 2720 770 2 1 {name=p121 sig_type=std_logic lab=DRV_ADDER[2]
spice_ignore=true}
C {lab_pin.sym} 3140 790 3 0 {name=p122 sig_type=std_logic lab=in_a
spice_ignore=true}
C {sg13g2_IOPadAnalog.sym} 2960 850 2 1 {name=x54
spice_ignore=true}
C {sg13g2_pr/bondpad.sym} 3220 850 1 1 {name=X55
model=bondpad
spiceprefix=X
size=80u
shape=0
padtype=0
spice_ignore=true}
C {lab_pin.sym} 2720 850 2 1 {name=p123 sig_type=std_logic lab=DRV_ADDER[3]
spice_ignore=true}
C {lab_pin.sym} 3140 870 3 0 {name=p124 sig_type=std_logic lab=in_a
spice_ignore=true}
C {sg13g2_IOPadAnalog.sym} 2960 930 2 1 {name=x56
spice_ignore=true}
C {sg13g2_pr/bondpad.sym} 3220 930 1 1 {name=X57
model=bondpad
spiceprefix=X
size=80u
shape=0
padtype=0
spice_ignore=true}
C {lab_pin.sym} 2720 930 2 1 {name=p125 sig_type=std_logic lab=DRV_ADDER[4]
spice_ignore=true}
C {lab_pin.sym} 3140 950 3 0 {name=p126 sig_type=std_logic lab=in_a
spice_ignore=true}
C {sg13g2_IOPadAnalog.sym} 2960 1090 2 1 {name=x58
spice_ignore=true}
C {sg13g2_pr/bondpad.sym} 3220 1090 1 1 {name=X59
model=bondpad
spiceprefix=X
size=80u
shape=0
padtype=0
spice_ignore=true}
C {lab_pin.sym} 2720 1090 2 1 {name=p127 sig_type=std_logic lab=DRV_ADDER[6]
spice_ignore=true}
C {lab_pin.sym} 3140 1110 3 0 {name=p128 sig_type=std_logic lab=in_a
spice_ignore=true}
C {sg13g2_IOPadAnalog.sym} 2960 1010 2 1 {name=x60
spice_ignore=true}
C {sg13g2_pr/bondpad.sym} 3220 1010 1 1 {name=X61
model=bondpad
spiceprefix=X
size=80u
shape=0
padtype=0
spice_ignore=true}
C {lab_pin.sym} 2720 1010 2 1 {name=p129 sig_type=std_logic lab=DRV_ADDER[5]
spice_ignore=true}
C {lab_pin.sym} 3140 1030 3 0 {name=p130 sig_type=std_logic lab=in_a
spice_ignore=true}
C {sg13g2_IOPadAnalog.sym} 2960 1170 2 1 {name=x62
spice_ignore=true}
C {sg13g2_pr/bondpad.sym} 3220 1170 1 1 {name=X63
model=bondpad
spiceprefix=X
size=80u
shape=0
padtype=0
spice_ignore=true}
C {lab_pin.sym} 2720 1170 2 1 {name=p131 sig_type=std_logic lab=DRV_ADDER[7]
spice_ignore=true}
C {lab_pin.sym} 3140 1190 3 0 {name=p132 sig_type=std_logic lab=in_a
spice_ignore=true}
C {sg13g2_pr/sub.sym} 920 -470 0 0 {name=l1 lab=sub!}
C {sg13g2_pr/sub.sym} 1040 -380 0 0 {name=l2 lab=sub!}
C {sg13g2_pr/sub.sym} 1150 -470 0 0 {name=l3 lab=sub!
}
C {sg13g2_pr/sub.sym} 1010 -160 0 0 {name=l4 lab=sub!
}
C {sg13g2_pr/sub.sym} 930 -160 0 0 {name=l5 lab=sub!
}
C {INV_D1.sym} 120 50 1 0 {name=x1[1:0]
}
C {INV_D2.sym} 120 230 1 0 {name=x2[1:0]
}
C {INV05.sym} 340 410 1 1 {name=x2
}
C {lab_wire.sym} 260 430 0 0 {name=p51 sig_type=std_logic lab=START
}
C {lab_pin.sym} 420 320 3 1 {name=p53 sig_type=std_logic lab=IO_vss
}
C {lab_pin.sym} 200 320 2 1 {name=p3 sig_type=std_logic lab=IO_vss
}
C {lab_pin.sym} 200 140 2 1 {name=p45 sig_type=std_logic lab=IO_vss
}
C {lab_pin.sym} 320 140 2 0 {name=p50 sig_type=std_logic lab=IO_vdd
}
C {lab_pin.sym} 540 320 2 0 {name=p47 sig_type=std_logic lab=IO_vdd
}
C {lab_pin.sym} 320 320 2 0 {name=p48 sig_type=std_logic lab=IO_vdd
}
C {lab_pin.sym} 260 50 0 1 {name=p49 sig_type=std_logic lab=DRV_START
}
C {INV_D1.sym} 640 40 1 0 {name=x3[1:0]
}
C {INV_D2.sym} 640 220 1 0 {name=x4[1:0]
}
C {INV05.sym} 860 400 1 1 {name=x10
}
C {lab_wire.sym} 780 420 0 0 {name=p52 sig_type=std_logic lab=STOP
}
C {lab_pin.sym} 940 310 3 1 {name=p54 sig_type=std_logic lab=IO_vss
}
C {lab_pin.sym} 720 310 2 1 {name=p57 sig_type=std_logic lab=IO_vss
}
C {lab_pin.sym} 720 130 2 1 {name=p58 sig_type=std_logic lab=IO_vss
}
C {lab_pin.sym} 840 130 2 0 {name=p59 sig_type=std_logic lab=IO_vdd
}
C {lab_pin.sym} 1060 310 2 0 {name=p60 sig_type=std_logic lab=IO_vdd
}
C {lab_pin.sym} 840 310 2 0 {name=p65 sig_type=std_logic lab=IO_vdd
}
C {lab_pin.sym} 780 40 0 1 {name=p69 sig_type=std_logic lab=DRV_STOP
}
C {INV_D1.sym} 1130 40 1 0 {name=x5[1:0]
}
C {INV_D2.sym} 1130 220 1 0 {name=x6[1:0]
}
C {INV05.sym} 1350 400 1 1 {name=x11
}
C {lab_wire.sym} 1270 420 0 0 {name=p76 sig_type=std_logic lab=RESET
}
C {lab_pin.sym} 1430 310 3 1 {name=p77 sig_type=std_logic lab=IO_vss
}
C {lab_pin.sym} 1210 310 2 1 {name=p78 sig_type=std_logic lab=IO_vss
}
C {lab_pin.sym} 1210 130 2 1 {name=p79 sig_type=std_logic lab=IO_vss
}
C {lab_pin.sym} 1330 130 2 0 {name=p80 sig_type=std_logic lab=IO_vdd
}
C {lab_pin.sym} 1550 310 2 0 {name=p81 sig_type=std_logic lab=IO_vdd
}
C {lab_pin.sym} 1330 310 2 0 {name=p82 sig_type=std_logic lab=IO_vdd
}
C {lab_pin.sym} 1270 40 0 1 {name=p83 sig_type=std_logic lab=DRV_RESET
}
C {INV_D1.sym} 120 600 1 0 {name=x7[1:0]
}
C {INV_D2.sym} 120 780 1 0 {name=x8[1:0]
}
C {INV05.sym} 340 960 1 1 {name=x12
}
C {lab_pin.sym} 420 870 3 1 {name=p85 sig_type=std_logic lab=IO_vss
}
C {lab_pin.sym} 200 870 2 1 {name=p86 sig_type=std_logic lab=IO_vss
}
C {lab_pin.sym} 200 690 2 1 {name=p103 sig_type=std_logic lab=IO_vss
}
C {lab_pin.sym} 320 690 2 0 {name=p104 sig_type=std_logic lab=IO_vdd
}
C {lab_pin.sym} 540 870 2 0 {name=p105 sig_type=std_logic lab=IO_vdd
}
C {lab_pin.sym} 320 870 2 0 {name=p106 sig_type=std_logic lab=IO_vdd
}
C {INV_D1.sym} 640 590 1 0 {name=x9[1:0]
}
C {INV_D2.sym} 640 770 1 0 {name=x10[1:0]
}
C {INV05.sym} 860 950 1 1 {name=x13
}
C {lab_pin.sym} 940 860 3 1 {name=p109 sig_type=std_logic lab=IO_vss
}
C {lab_pin.sym} 720 860 2 1 {name=p110 sig_type=std_logic lab=IO_vss
}
C {lab_pin.sym} 720 680 2 1 {name=p111 sig_type=std_logic lab=IO_vss
}
C {lab_pin.sym} 840 680 2 0 {name=p112 sig_type=std_logic lab=IO_vdd
}
C {lab_pin.sym} 1060 860 2 0 {name=p113 sig_type=std_logic lab=IO_vdd
}
C {lab_pin.sym} 840 860 2 0 {name=p114 sig_type=std_logic lab=IO_vdd
}
C {INV_D1.sym} 1130 590 1 0 {name=x11[1:0]
}
C {INV_D2.sym} 1130 770 1 0 {name=x12[1:0]
}
C {INV05.sym} 1350 950 1 1 {name=x14
}
C {lab_pin.sym} 1430 860 3 1 {name=p117 sig_type=std_logic lab=IO_vss
}
C {lab_pin.sym} 1210 860 2 1 {name=p118 sig_type=std_logic lab=IO_vss
}
C {lab_pin.sym} 1210 680 2 1 {name=p133 sig_type=std_logic lab=IO_vss
}
C {lab_pin.sym} 1330 680 2 0 {name=p134 sig_type=std_logic lab=IO_vdd
}
C {lab_pin.sym} 1550 860 2 0 {name=p135 sig_type=std_logic lab=IO_vdd
}
C {lab_pin.sym} 1330 860 2 0 {name=p136 sig_type=std_logic lab=IO_vdd
}
C {INV_D1.sym} 130 1100 1 0 {name=x13[1:0]
}
C {INV_D2.sym} 130 1280 1 0 {name=x14[1:0]
}
C {INV05.sym} 350 1460 1 1 {name=x17
}
C {lab_pin.sym} 430 1370 3 1 {name=p139 sig_type=std_logic lab=IO_vss
}
C {lab_pin.sym} 210 1370 2 1 {name=p140 sig_type=std_logic lab=IO_vss
}
C {lab_pin.sym} 210 1190 2 1 {name=p141 sig_type=std_logic lab=IO_vss
}
C {lab_pin.sym} 330 1190 2 0 {name=p142 sig_type=std_logic lab=IO_vdd
}
C {lab_pin.sym} 550 1370 2 0 {name=p143 sig_type=std_logic lab=IO_vdd
}
C {lab_pin.sym} 330 1370 2 0 {name=p144 sig_type=std_logic lab=IO_vdd
}
C {lab_pin.sym} 270 1100 0 1 {name=p145 sig_type=std_logic lab=ADDER[3]
}
C {INV_D1.sym} 650 1090 1 0 {name=x15[1:0]
}
C {INV_D2.sym} 650 1270 1 0 {name=x16[1:0]
}
C {INV05.sym} 870 1450 1 1 {name=x19
}
C {lab_pin.sym} 950 1360 3 1 {name=p147 sig_type=std_logic lab=IO_vss
}
C {lab_pin.sym} 730 1360 2 1 {name=p148 sig_type=std_logic lab=IO_vss
}
C {lab_pin.sym} 730 1180 2 1 {name=p149 sig_type=std_logic lab=IO_vss
}
C {lab_pin.sym} 850 1180 2 0 {name=p150 sig_type=std_logic lab=IO_vdd
}
C {lab_pin.sym} 1070 1360 2 0 {name=p151 sig_type=std_logic lab=IO_vdd
}
C {lab_pin.sym} 850 1360 2 0 {name=p152 sig_type=std_logic lab=IO_vdd
}
C {lab_pin.sym} 790 1090 0 1 {name=p153 sig_type=std_logic lab=ADDER[4]
}
C {INV_D1.sym} 1140 1090 1 0 {name=x17[1:0]
}
C {INV_D2.sym} 1140 1270 1 0 {name=x18[1:0]
}
C {INV05.sym} 1360 1450 1 1 {name=x20
}
C {lab_pin.sym} 1440 1360 3 1 {name=p155 sig_type=std_logic lab=IO_vss
}
C {lab_pin.sym} 1220 1360 2 1 {name=p156 sig_type=std_logic lab=IO_vss
}
C {lab_pin.sym} 1220 1180 2 1 {name=p157 sig_type=std_logic lab=IO_vss
}
C {lab_pin.sym} 1340 1180 2 0 {name=p158 sig_type=std_logic lab=IO_vdd
}
C {lab_pin.sym} 1560 1360 2 0 {name=p159 sig_type=std_logic lab=IO_vdd
}
C {lab_pin.sym} 1340 1360 2 0 {name=p160 sig_type=std_logic lab=IO_vdd
}
C {lab_pin.sym} 1280 1090 0 1 {name=p161 sig_type=std_logic lab=ADDER[5]
}
C {INV_D1.sym} 130 1560 1 0 {name=x19[1:0]
}
C {INV_D2.sym} 130 1740 1 0 {name=x20[1:0]
}
C {INV05.sym} 350 1920 1 1 {name=x21
}
C {lab_wire.sym} 270 1940 0 0 {name=p162 sig_type=std_logic lab=DRV_ADDER[6]
}
C {lab_pin.sym} 430 1830 3 1 {name=p163 sig_type=std_logic lab=IO_vss
}
C {lab_pin.sym} 210 1830 2 1 {name=p164 sig_type=std_logic lab=IO_vss
}
C {lab_pin.sym} 210 1650 2 1 {name=p165 sig_type=std_logic lab=IO_vss
}
C {lab_pin.sym} 330 1650 2 0 {name=p166 sig_type=std_logic lab=IO_vdd
}
C {lab_pin.sym} 550 1830 2 0 {name=p167 sig_type=std_logic lab=IO_vdd
}
C {lab_pin.sym} 330 1830 2 0 {name=p168 sig_type=std_logic lab=IO_vdd
}
C {lab_pin.sym} 270 1560 0 1 {name=p169 sig_type=std_logic lab=ADDER[6]
}
C {INV_D1.sym} 650 1550 1 0 {name=x21[1:0]
}
C {INV_D2.sym} 650 1730 1 0 {name=x22[1:0]
}
C {INV05.sym} 870 1910 1 1 {name=x22
}
C {lab_wire.sym} 790 1930 0 0 {name=p170 sig_type=std_logic lab=DRV_ADDER[7]
}
C {lab_pin.sym} 950 1820 3 1 {name=p171 sig_type=std_logic lab=IO_vss
}
C {lab_pin.sym} 730 1820 2 1 {name=p172 sig_type=std_logic lab=IO_vss
}
C {lab_pin.sym} 730 1640 2 1 {name=p173 sig_type=std_logic lab=IO_vss
}
C {lab_pin.sym} 850 1640 2 0 {name=p174 sig_type=std_logic lab=IO_vdd
}
C {lab_pin.sym} 1070 1820 2 0 {name=p175 sig_type=std_logic lab=IO_vdd
}
C {lab_pin.sym} 850 1820 2 0 {name=p176 sig_type=std_logic lab=IO_vdd
}
C {lab_pin.sym} 790 1550 0 1 {name=p177 sig_type=std_logic lab=ADDER[7]
}
C {lab_pin.sym} 260 600 0 1 {name=p107 sig_type=std_logic lab=ADDER[0]
}
C {lab_pin.sym} 780 590 0 1 {name=p115 sig_type=std_logic lab=ADDER[1]
}
C {lab_pin.sym} 1270 590 0 1 {name=p137 sig_type=std_logic lab=ADDER[2]
}
C {lab_pin.sym} 780 970 0 1 {name=p108 sig_type=std_logic lab=DRV_ADDER[1]
}
C {lab_pin.sym} 1270 970 0 1 {name=p116 sig_type=std_logic lab=DRV_ADDER[2]
}
C {lab_pin.sym} 1280 1470 0 1 {name=p138 sig_type=std_logic lab=DRV_ADDER[5]
}
C {lab_pin.sym} 790 1470 0 1 {name=p146 sig_type=std_logic lab=DRV_ADDER[4]
}
C {lab_pin.sym} 270 1480 0 1 {name=p154 sig_type=std_logic lab=DRV_ADDER[3]
}
C {lab_pin.sym} 260 980 0 1 {name=p84 sig_type=std_logic lab=DRV_ADDER[0]
}
C {res.sym} 2380 1560 1 0 {name=R1
value=50
footprint=1206
device=resistor
m=1
spice_ignore=true}
C {lab_pin.sym} 2310 1560 3 1 {name=p178 sig_type=std_logic lab=RES_IO_vdd
spice_ignore=true}
C {res.sym} 2730 1560 1 0 {name=R2
value=50
footprint=1206
device=resistor
m=1
spice_ignore=true}
C {lab_pin.sym} 2790 1560 1 0 {name=p179 sig_type=std_logic lab=RES_IO_vss
spice_ignore=true}
C {res.sym} 2410 280 1 0 {name=R3
value=50
footprint=1206
device=resistor
m=1
spice_ignore=true}
C {res.sym} 2670 280 1 0 {name=R4
value=50
footprint=1206
device=resistor
m=1
spice_ignore=true}
C {lab_pin.sym} 2330 280 1 0 {name=p180 sig_type=std_logic lab=RES_IO_iovdd
spice_ignore=true}
C {lab_pin.sym} 2740 280 1 0 {name=p181 sig_type=std_logic lab=RES_IO_iovss
spice_ignore=true}
C {vsource.sym} 1210 -830 0 0 {name=V1 value=1.2}
C {gnd.sym} 1210 -800 0 0 {name=l6 lab=GND}
C {lab_pin.sym} 1210 -870 1 0 {name=p182 sig_type=std_logic lab=IO_vdd}
C {vsource.sym} 1270 -830 0 0 {name=V4 value=3.3
}
C {gnd.sym} 1270 -800 0 0 {name=l7 lab=GND}
C {lab_pin.sym} 1270 -870 1 0 {name=p183 sig_type=std_logic lab=IO_iovdd}
C {vsource.sym} 1130 -830 0 0 {name=V5 value=0 savecurrent=false}
C {gnd.sym} 1130 -800 0 0 {name=l8 lab=GND}
C {lab_pin.sym} 1130 -870 1 0 {name=p184 sig_type=std_logic lab=IO_vss}
C {vsource.sym} 1070 -830 0 0 {name=V7 value=0 savecurrent=false}
C {gnd.sym} 1070 -800 0 0 {name=l9 lab=GND}
C {lab_pin.sym} 1070 -870 1 0 {name=p185 sig_type=std_logic lab=IO_iovss}
C {code.sym} 1680 -1130 0 0 {name=NGSPICE2 only_toplevel=true 
value="
.param temp=65

* Agrega una resistencia gigante en los nodos flotantes
.OPTION RSHUNT=1e9

* Agrega un cap pequeño a cada nodo
* evita dv/dt infinito
.OPTION CSHUNT=1e-15

* Conducción minima en Junturas de diodos
* diodos duros
.options gmin=1e-10

*resistencia serie global (a fuentes ideales e inductores)
.option rseries = 1e-4

* integrador robusto
* ayuda a resolver la no linealidad
.options method=gear

* limita el orden del integrador
* limita cuantos pasos anteriores usa el integrador
.options maxord=2

* tolerancias : error relativo (%) - error absoluto en voltaje - error absoluto en corriente
.options reltol=1e-2 vabstol=1e-4 iabstol=1e-9

* paciencia del solver: DC - Transitorio - Newton interno

.option ITL1=1000 ITL2=400 ITL4=500




* .nodeset all=0
.ic v(START)=0 v(STOP)=0 v(DECLK)=0 v(DECLK2)=0 v(RESET)=0
.ic v(START_PAD)=0 v(STOP_PAD)=0 v(RESET_PAD)=0
.ic v(IO_iovss)=0 v(IO_iovdd)=3.3 v(IO_vss)=0 v(IO_vdd)=1.2
.ic v(IN0) v(IN1) v(IN2)
.ic v(K0) v(K1) v(K2)
.ic v("D0[0]")=0 v("D0[1]")=0 v("D0[2]")=0 
.ic v("D0[3]")=0 v("D0[4]")=0 v("D0[5]")=0 
.ic v("D1[0]")=0 v("D1[1]")=0 v("D1[2]")=0
.ic v("D1[3]")=0 v("D1[4]")=0 v("D1[5]")=0
.ic v("D2[0]")=0 v("D2[1]")=0 v("D2[2]")=0
.ic v("D2[3]")=0 v("D2[4]")=0 v("D2[5]")=0
.ic v("C0_B[0]")=0 v("C1_B[0]")=0 v("C2_B[0]")=0
.ic v("C0_B[1]")=0 v("C1_B[1]")=0 v("C2_B[1]")=0
.ic v("C0_B[2]")=0 v("C1_B[2]")=0 v("C2_B[2]")=0
.ic v("C0_B[3]")=0 v("C1_B[3]")=0 v("C2_B[3]")=0
.ic v("C0_B[4]")=0 v("C1_B[4]")=0 v("C2_B[4]")=0
.ic v("C0_B[5]")=0 v("C1_B[5]")=0 v("C2_B[5]")=0
.ic v("S1[0]")=0 v("S1[1]")=0 v("S1[2]")=0 
.ic v("S1[3]")=0 v("S1[4]")=0 v("S1[5]")=0 
.ic v(COUT1)=0 
.ic v("S2[0]")=0 v("S2[1]")=0 v("S2[2]")=0 
.ic v("S2[3]")=0 v("S2[4]")=0 v("S2[5]") v("S2[6]")=0
.ic v(COUT2)=0
.ic v("ADDER[0]")=0 v("ADDER[1]")=0 v("ADDER[2]")=0
.ic v("ADDER[3]")=0 v("ADDER[4]")=0 v("ADDER[5]")=0
.ic v("ADDER[6]")=0 v("ADDER[7]")=0

.control
* Sources
save v(START) v(STOP) v(DECLK) v(DECLK2) v(RESET)
save v(START_PAD) v(STOP_PAD) v(RESET_PAD)
save v(IO_iovss) v(IO_iovdd) v(IO_vss) v(IO_vdd)

* GRO
save v(IN0) v(IN1) v(IN2)

* Buffers
save v(K0) v(K1) v(K2)

* Counters Reg (BUS → SIEMPRE con comillas)
save v("D0[0]") v("D0[1]") v("D0[2]") 
save v("D0[3]") v("D0[4]") v("D0[5]") 
save v("D1[0]") v("D1[1]") v("D1[2]")
save v("D1[3]") v("D1[4]") v("D1[5]")
save v("D2[0]") v("D2[1]") v("D2[2]")
save v("D2[3]") v("D2[4]") v("D2[5]")


* NUEVO: C0_B[4], C1_B[4], C2_B[4] (bits 0 a 5)
save v("C0_B[0]") v("C1_B[0]") v("C2_B[0]")
save v("C0_B[1]") v("C1_B[1]") v("C2_B[1]")
save v("C0_B[2]") v("C1_B[2]") v("C2_B[2]")
save v("C0_B[3]") v("C1_B[3]") v("C2_B[3]")
save v("C0_B[4]") v("C1_B[4]") v("C2_B[4]")
save v("C0_B[5]") v("C1_B[5]") v("C2_B[5]")



* FA
save v("S1[0]") v("S1[1]") v("S1[2]") 
save v("S1[3]") v("S1[4]") v("S1[5]") 
save v(COUT1) 
save v("S2[0]") v("S2[1]") v("S2[2]") 
save v("S2[3]") v("S2[4]") v("S2[5]") v("S2[6]")
save v(COUT2)

* FA Regs
save v("ADDER[0]") v("ADDER[1]") v("ADDER[2]")
save v("ADDER[3]") v("ADDER[4]") v("ADDER[5]")
save v("ADDER[6]") v("ADDER[7]")

* uic: saltearse el punto de operación
*tran 5p 100n 0 5p uic
* .tran <tstep> <tstop> [tstart] [tmax] [uic]
* tmax Limita el paso máximo que puede usar el integrador
tran 10p 110n 0 95p

write tb_TOP_io.raw

.endc
"
}
C {code.sym} 1890 -1140 0 0 {name=NGSPICE3 only_toplevel=true 
value="
.param temp=65

.option RSHUNT=1e9
.option CSHUNT=1e-15
.option gmin=1e-12
.option rseries=1e-2

.options method=gear maxord=2
.options reltol=2e-2 vabstol=2e-4 iabstol=2e-9
.option ITL1=600 ITL2=200 ITL4=300

* Evitá nodeset global
.nodeset v(START_PAD)=0 v(STOP_PAD)=0 v(RESET_PAD)=0
.nodeset v(IO_iovdd)=3.3 v(IO_iovss)=0 v(IO_vdd)=1.2 v(IO_vss)=0

.ic v(DRV_START)=0 v(DRV_STOP)=0

.control
* Guardar solo lo necesario
save v(START) v(STOP) v(DECLK) v(DECLK2) v(RESET)
save v(START_PAD) v(STOP_PAD) v(RESET_PAD)
save v(IO_iovss) v(IO_iovdd) v(IO_vss) v(IO_vdd)
save v(IN0) v(IN1) v(IN2)
save v(K0) v(K1) v(K2)

* Counters outputs (buses: SIEMPRE con comillas)
save v("D0[0]") v("D0[1]") v("D0[2]") v("D0[3]") v("D0[4]") v("D0[5]")
save v("D1[0]") v("D1[1]") v("D1[2]") v("D1[3]") v("D1[4]") v("D1[5]")
save v("D2[0]") v("D2[1]") v("D2[2]") v("D2[3]") v("D2[4]") v("D2[5]")

* NUEVO: C0_B[4], C1_B[4], C2_B[4] (bits 0 a 5)
save v("C0_B[4]") v("C1_B[4]") v("C2_B[4]")

* FA / adders (también con comillas)
save v("S1[0]") v("S1[1]") v("S1[2]") v("S1[3]") v("S1[4]") v("S1[5]") v(COUT1)
save v("S2[0]") v("S2[1]") v("S2[2]") v("S2[3]") v("S2[4]") v("S2[5]") v("S2[6]") v(COUT2)

save v("ADDER[0]") v("ADDER[1]") v("ADDER[2]") v("ADDER[3]") v("ADDER[4]") v("ADDER[5]") v("ADDER[6]") v("ADDER[7]")

* ---- Truco pro: 2 etapas ----
* Etapa 1: arranque (0 a 5ns) con paso máximo chico y sin OP
tran 20p 5n 0 20p uic

* Etapa 2: continuar desde 5ns hasta 110ns con tmax más grande
tran 20p 110n 5n 200p

write tb_TOP_io.raw
.endc

"
spice_ignore=true}
